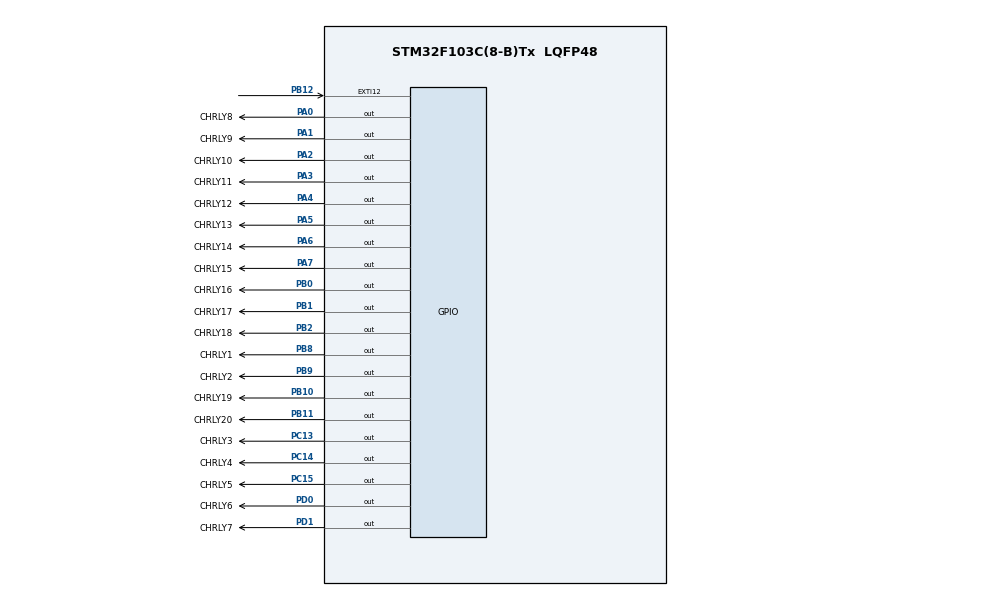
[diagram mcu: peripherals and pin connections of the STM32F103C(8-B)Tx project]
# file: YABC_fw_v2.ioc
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Mcu.Family=STM32F1
Mcu.Name=STM32F103C(8-B)Tx
Mcu.Package=LQFP48
NVIC.EXTI15_10_IRQn=true\:0\:0\:false\:false\:true\:true\:true\:true
NVIC.PriorityGroup=NVIC_PRIORITYGROUP_4
NVIC.TIM1_UP_IRQn=true\:0\:0\:false\:false\:true\:true\:true\:true
NVIC.TIM2_IRQn=true\:0\:0\:false\:false\:true\:true\:true\:true
PA0-WKUP.GPIO_Label=CHRLY8
PA0-WKUP.PinState=GPIO_PIN_RESET
PA0-WKUP.Signal=GPIO_Output
PA1.GPIO_Label=CHRLY9
PA1.PinState=GPIO_PIN_RESET
PA1.Signal=GPIO_Output
PA13.Mode=Serial_Wire
PA13.Signal=SYS_JTMS-SWDIO
PA14.Mode=Serial_Wire
PA14.Signal=SYS_JTCK-SWCLK
PA2.GPIO_Label=CHRLY10
PA2.PinState=GPIO_PIN_RESET
PA2.Signal=GPIO_Output
PA3.GPIO_Label=CHRLY11
PA3.PinState=GPIO_PIN_RESET
PA3.Signal=GPIO_Output
PA4.GPIO_Label=CHRLY12
PA4.PinState=GPIO_PIN_RESET
PA4.Signal=GPIO_Output
PA5.GPIO_Label=CHRLY13
PA5.PinState=GPIO_PIN_RESET
PA5.Signal=GPIO_Output
PA6.GPIO_Label=CHRLY14
PA6.PinState=GPIO_PIN_RESET
PA6.Signal=GPIO_Output
PA7.GPIO_Label=CHRLY15
PA7.PinState=GPIO_PIN_RESET
PA7.Signal=GPIO_Output
PB0.GPIO_Label=CHRLY16
PB0.PinState=GPIO_PIN_RESET
PB0.Signal=GPIO_Output
PB1.GPIO_Label=CHRLY17
PB1.PinState=GPIO_PIN_RESET
PB1.Signal=GPIO_Output
PB10.GPIO_Label=CHRLY19
PB10.PinState=GPIO_PIN_RESET
PB10.Signal=GPIO_Output
PB11.GPIO_Label=CHRLY20
PB11.PinState=GPIO_PIN_RESET
PB11.Signal=GPIO_Output
PB12.GPIO_ModeDefaultEXTI=GPIO_MODE_IT_RISING_FALLING
PB12.GPIO_PuPd=GPIO_PULLUP
PB12.Signal=GPXTI12
PB2.GPIO_Label=CHRLY18
PB2.PinState=GPIO_PIN_RESET
PB2.Signal=GPIO_Output
PB8.GPIO_Label=CHRLY1
PB8.PinState=GPIO_PIN_SET
PB8.Signal=GPIO_Output
PB9.GPIO_Label=CHRLY2
PB9.PinState=GPIO_PIN_RESET
PB9.Signal=GPIO_Output
PC13-TAMPER-RTC.GPIO_Label=CHRLY3
PC13-TAMPER-RTC.PinState=GPIO_PIN_RESET
PC13-TAMPER-RTC.Signal=GPIO_Output
PC14-OSC32_IN.GPIO_Label=CHRLY4
PC14-OSC32_IN.PinState=GPIO_PIN_RESET
PC14-OSC32_IN.Signal=GPIO_Output
PC15-OSC32_OUT.GPIO_Label=CHRLY5
PC15-OSC32_OUT.PinState=GPIO_PIN_RESET
PC15-OSC32_OUT.Signal=GPIO_Output
PD0-OSC_IN.GPIO_Label=CHRLY6
PD0-OSC_IN.PinState=GPIO_PIN_RESET
PD0-OSC_IN.Signal=GPIO_Output
PD1-OSC_OUT.GPIO_Label=CHRLY7
PD1-OSC_OUT.PinState=GPIO_PIN_RESET
PD1-OSC_OUT.Signal=GPIO_Output
ProjectManager.HeapSize=0x200
ProjectManager.StackSize=0x400
ProjectManager.TargetToolchain=STM32CubeIDE
RCC.AHBCLKDivider=RCC_SYSCLK_DIV2
RCC.AHBFreq_Value=4000000
RCC.APB1Freq_Value=4000000
RCC.APB1TimFreq_Value=4000000
RCC.APB2Freq_Value=4000000
RCC.APB2TimFreq_Value=4000000
RCC.HCLKFreq_Value=4000000
RCC.SYSCLKFreq_VALUE=8000000
RCC.SYSCLKSource=RCC_SYSCLKSOURCE_PLLCLK
RCC.USBFreq_Value=8000000
TIM1.Period=8
TIM1.Prescaler=49
TIM2.Period=20
TIM2.Prescaler=3999
VP_TIM1_VS_ClockSourceINT.Mode=Internal
VP_TIM2_VS_ClockSourceINT.Mode=Internal
board=custom

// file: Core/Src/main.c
/* USER CODE BEGIN Header */
/**
  ******************************************************************************
  * @file           : main.c
  * @brief          : Optimized Main program body for Charlieplexing (4MHz Low Power)
  ******************************************************************************
  */
/* USER CODE END Header */

#include "main.h"
#include <string.h>

// Ensure this header defines 'video_frames[ANIMATION_FRAMES][20][19]'
// #include "animations.h"

/* USER CODE BEGIN PTD */

// Represents the register state for one specific row/bit-plane
typedef struct {
    uint32_t PortA_CRL;
    // uint32_t PortA_CRH; // EXCLUDED to protect SWD (PA13/PA14)
    uint32_t PortA_ODR;

    uint32_t PortB_CRL;
    uint32_t PortB_CRH;
    uint32_t PortB_ODR;

    uint32_t PortC_CRL;
    uint32_t PortC_CRH;
    uint32_t PortC_ODR;

    uint32_t PortD_CRL;
    uint32_t PortD_CRH;
    uint32_t PortD_ODR;
} RowRegisterState;

// Physical Pin Definition
typedef struct {
    GPIO_TypeDef* port;
    uint8_t pinIndex;
} PinDef;

// Hardware Map for a Row
typedef struct {
    PinDef anode;
    PinDef cathodes[18];
} HardwareRowDef;

/* USER CODE END PTD */

/* USER CODE BEGIN PD */
#define COLOR_DEPTH 2    // 2-bit BCM (4 brightness levels: 0, 1, 2, 3)
#define ROW_COUNT 19
#define COL_COUNT 18

#define ANIMATION_FRAMES 1
/* USER CODE END PD */

TIM_HandleTypeDef htim1;
TIM_HandleTypeDef htim2;

/* USER CODE BEGIN PV */

// --- GLOBAL BUFFERS ---
// The ISR reads from here. Main loop writes to here.
RowRegisterState frameBufferLUT[ROW_COUNT][COLOR_DEPTH];

uint32_t bitDuration[COLOR_DEPTH];
volatile int current_frame_idx = 0;
volatile uint8_t update_frame_flag = 1; // Flag to trigger calculation

volatile uint8_t system_active = 1;
uint32_t last_activity_time = 0;

// --- HARDWARE PIN MAPPING ---
// The exact physical order of your Charlieplexing network (Pins 1-19)
const PinDef ALL_PINS[19] = {
    {GPIOB, 0}, {GPIOB, 1}, {GPIOB, 2},  {GPIOB, 3},  {GPIOB, 4},
    {GPIOB, 5}, {GPIOB, 6}, {GPIOB, 7},  {GPIOB, 8},  {GPIOB, 9},
    {GPIOB, 10},{GPIOB, 11},{GPIOB, 12}, {GPIOB, 13}, {GPIOB, 14},
    {GPIOB, 15},{GPIOC, 13},{GPIOC, 14}, {GPIOC, 15}
};

uint32_t video_frames[1][20][19] = {
	{0x0D, 0x1A, 0x27, 0x34, 0x41, 0x4E, 0x5B, 0x68, 0x075, 0x82, 0x8F, 0x9C, 0xA9, 0xB6, 0xC3, 0xD0, 0xDD, 0xEA, 0xF7},
	{0x0D, 0x1A, 0x27, 0x34, 0x41, 0x4E, 0x5B, 0x68, 0x075, 0x82, 0x8F, 0x9C, 0xA9, 0xB6, 0xC3, 0xD0, 0xDD, 0xEA, 0xF7},
	{0x0D, 0x1A, 0x27, 0x34, 0x41, 0x4E, 0x5B, 0x68, 0x075, 0x82, 0x8F, 0x9C, 0xA9, 0xB6, 0xC3, 0xD0, 0xDD, 0xEA, 0xF7},
	{0x0D, 0x1A, 0x27, 0x34, 0x41, 0x4E, 0x5B, 0x68, 0x075, 0x82, 0x8F, 0x9C, 0xA9, 0xB6, 0xC3, 0xD0, 0xDD, 0xEA, 0xF7},
	{0x0D, 0x1A, 0x27, 0x34, 0x41, 0x4E, 0x5B, 0x68, 0x075, 0x82, 0x8F, 0x9C, 0xA9, 0xB6, 0xC3, 0xD0, 0xDD, 0xEA, 0xF7},
	{0x0D, 0x1A, 0x27, 0x34, 0x41, 0x4E, 0x5B, 0x68, 0x075, 0x82, 0x8F, 0x9C, 0xA9, 0xB6, 0xC3, 0xD0, 0xDD, 0xEA, 0xF7},
	{0x0D, 0x1A, 0x27, 0x34, 0x41, 0x4E, 0x5B, 0x68, 0x075, 0x82, 0x8F, 0x9C, 0xA9, 0xB6, 0xC3, 0xD0, 0xDD, 0xEA, 0xF7},
	{0x0D, 0x1A, 0x27, 0x34, 0x41, 0x4E, 0x5B, 0x68, 0x075, 0x82, 0x8F, 0x9C, 0xA9, 0xB6, 0xC3, 0xD0, 0xDD, 0xEA, 0xF7},
	{0x0D, 0x1A, 0x27, 0x34, 0x41, 0x4E, 0x5B, 0x68, 0x075, 0x82, 0x8F, 0x9C, 0xA9, 0xB6, 0xC3, 0xD0, 0xDD, 0xEA, 0xF7},
	{0x0D, 0x1A, 0x27, 0x34, 0x41, 0x4E, 0x5B, 0x68, 0x075, 0x82, 0x8F, 0x9C, 0xA9, 0xB6, 0xC3, 0xD0, 0xDD, 0xEA, 0xF7},
	{0x0D, 0x1A, 0x27, 0x34, 0x41, 0x4E, 0x5B, 0x68, 0x075, 0x82, 0x8F, 0x9C, 0xA9, 0xB6, 0xC3, 0xD0, 0xDD, 0xEA, 0xF7},
	{0x0D, 0x1A, 0x27, 0x34, 0x41, 0x4E, 0x5B, 0x68, 0x075, 0x82, 0x8F, 0x9C, 0xA9, 0xB6, 0xC3, 0xD0, 0xDD, 0xEA, 0xF7},
	{0x0D, 0x1A, 0x27, 0x34, 0x41, 0x4E, 0x5B, 0x68, 0x075, 0x82, 0x8F, 0x9C, 0xA9, 0xB6, 0xC3, 0xD0, 0xDD, 0xEA, 0xF7},
	{0x0D, 0x1A, 0x27, 0x34, 0x41, 0x4E, 0x5B, 0x68, 0x075, 0x82, 0x8F, 0x9C, 0xA9, 0xB6, 0xC3, 0xD0, 0xDD, 0xEA, 0xF7},
	{0x0D, 0x1A, 0x27, 0x34, 0x41, 0x4E, 0x5B, 0x68, 0x075, 0x82, 0x8F, 0x9C, 0xA9, 0xB6, 0xC3, 0xD0, 0xDD, 0xEA, 0xF7},
	{0x0D, 0x1A, 0x27, 0x34, 0x41, 0x4E, 0x5B, 0x68, 0x075, 0x82, 0x8F, 0x9C, 0xA9, 0xB6, 0xC3, 0xD0, 0xDD, 0xEA, 0xF7},
	{0x0D, 0x1A, 0x27, 0x34, 0x41, 0x4E, 0x5B, 0x68, 0x075, 0x82, 0x8F, 0x9C, 0xA9, 0xB6, 0xC3, 0xD0, 0xDD, 0xEA, 0xF7},
	{0x0D, 0x1A, 0x27, 0x34, 0x41, 0x4E, 0x5B, 0x68, 0x075, 0x82, 0x8F, 0x9C, 0xA9, 0xB6, 0xC3, 0xD0, 0xDD, 0xEA, 0xF7},
	{0x0D, 0x1A, 0x27, 0x34, 0x41, 0x4E, 0x5B, 0x68, 0x075, 0x82, 0x8F, 0x9C, 0xA9, 0xB6, 0xC3, 0xD0, 0xDD, 0xEA, 0xF7},
	{0x0D, 0x1A, 0x27, 0x34, 0x41, 0x4E, 0x5B, 0x68, 0x075, 0x82, 0x8F, 0x9C, 0xA9, 0xB6, 0xC3, 0xD0, 0xDD, 0xEA, 0xF7}
};

/* USER CODE END PV */

void SystemClock_Config(void);
static void MX_GPIO_Init(void);
static void MX_TIM1_Init(void);
static void MX_TIM2_Init(void);

/* USER CODE BEGIN PFP */
void initBitDurationLUT(void);
void GetHardwareRow(int rowIndex, HardwareRowDef *rowDef);
void PrecomputeFrame(void);
/* USER CODE END PFP */

int main(void)
{
  HAL_Init();

  // 1. Configure System Clock to 4 MHz (Low Power)
  SystemClock_Config();

  initBitDurationLUT();

  MX_GPIO_Init();
  MX_TIM1_Init();
  MX_TIM2_Init();

  // 2. Initial Frame Calculation
  PrecomputeFrame();

  // 3. Start Timers
  HAL_TIM_Base_Start_IT(&htim1); // LED Refresh (High Speed)
  HAL_TIM_Base_Start_IT(&htim2); // Animation Tick (Low Speed)

  last_activity_time = HAL_GetTick();

  while (1)
  {
    // --- SLEEP LOGIC (10 Seconds Timeout) ---
    if(system_active && (HAL_GetTick() - last_activity_time > 10000)){
        system_active = 0;

        // Disable Timers to stop interrupts
        HAL_TIM_Base_Stop_IT(&htim1);
        HAL_TIM_Base_Stop_IT(&htim2);

        // Turn off all LEDs (Reset ODRs to safe state)
        GPIOA->ODR = (1<<0);  // Keep PA0 Pull-Up active! (New wakeup button)
        GPIOB->ODR = 0;
        GPIOC->ODR = 0;
        GPIOD->ODR = 0;

        // Enter Stop Mode
        HAL_SuspendTick();
        HAL_PWR_EnterSTOPMode(PWR_LOWPOWERREGULATOR_ON, PWR_STOPENTRY_WFI);

        // --- WAKE UP POINT ---
        SystemClock_Config(); // Restore 4 MHz clock
        HAL_ResumeTick();

        system_active = 1;
        last_activity_time = HAL_GetTick();

        // Restart Timers
        HAL_TIM_Base_Start_IT(&htim1);
        HAL_TIM_Base_Start_IT(&htim2);
    }

    // --- RENDER LOGIC ---
    // Only calculate when TIM2 says the frame has changed
    if(system_active && update_frame_flag) {
        PrecomputeFrame();
        update_frame_flag = 0;
    }
  }
}

/**
  * @brief  ISR for LED Refresh (TIM1)
  * @note   Extremely optimized register dump. No logic here.
  */
void HAL_TIM_PeriodElapsedCallback(TIM_HandleTypeDef* htim)
{
    static int row = 0;
    static int bit = 0;

    if(htim->Instance == TIM1) // LED Refresh
    {
        // Pointer to the pre-calculated register state
        RowRegisterState *state = &frameBufferLUT[row][bit];

        // 1. Dump Registers (Takes ~20 cycles)
        GPIOA->CRL = state->PortA_CRL;
        // GPIOA->CRH = state->PortA_CRH; // DISABLED FOR SWD SAFETY
        GPIOA->ODR = state->PortA_ODR;

        GPIOB->CRL = state->PortB_CRL;
        GPIOB->CRH = state->PortB_CRH;
        GPIOB->ODR = state->PortB_ODR;

        GPIOC->CRL = state->PortC_CRL;
        GPIOC->CRH = state->PortC_CRH;
        GPIOC->ODR = state->PortC_ODR;

        GPIOD->CRL = state->PortD_CRL;
        GPIOD->CRH = state->PortD_CRH;
        GPIOD->ODR = state->PortD_ODR;

        // 2. Advance Counters
        row++;
        if(row >= ROW_COUNT)
        {
            row = 0;
            bit++;
            if(bit >= COLOR_DEPTH) bit = 0;

            TIM1->ARR = bitDuration[bit]; // Update BAM timing
        }
    }

    if(htim->Instance == TIM2) // Animation Tick
    {
        current_frame_idx++;
        if (current_frame_idx >= ANIMATION_FRAMES) {
            current_frame_idx = 0;
        }
        update_frame_flag = 1; // Tell Main loop to calculate next frame
    }
}

/**
  * @brief  Calculates the LUT for the current frame based on 8-bit input.
  * Runs in Main Loop.
  */
void PrecomputeFrame(void) {
    const uint32_t DEFAULT_CRL = 0x44444444;
    const uint32_t DEFAULT_CRH = 0x44444444;

    // SAFETY FOR PA0: Default CRL for Port A must set Pin 0 to Input Pull-Up/Down (0x8)
    const uint32_t PORTA_CRL_SAFE = 0x44444448;
    const uint32_t PORTA_ODR_SAFE = (1 << 0); // Pull-Up selected

    HardwareRowDef rowHardware;

    // Pre-calculate the divisor for thresholding
    // For Depth 2 (4 levels): 256 / 4 = 64.
    uint8_t divisor = 256 / (1 << COLOR_DEPTH);

    for(int row = 0; row < ROW_COUNT; row++) {
        GetHardwareRow(row, &rowHardware);

        for(int bitPlane = 0; bitPlane < COLOR_DEPTH; bitPlane++) {

            RowRegisterState *state = &frameBufferLUT[row][bitPlane];

            // 1. Reset State to Safe Defaults
            state->PortA_CRL = PORTA_CRL_SAFE; // PA0 Safety
            state->PortA_ODR = PORTA_ODR_SAFE; // PA0 Safety

            state->PortB_CRL = DEFAULT_CRL;
            state->PortB_CRH = DEFAULT_CRH;
            state->PortB_ODR = 0;

            state->PortC_CRL = DEFAULT_CRL;
            state->PortC_CRH = DEFAULT_CRH;
            state->PortC_ODR = 0;

            state->PortD_CRL = DEFAULT_CRL;
            state->PortD_CRH = DEFAULT_CRH;
            state->PortD_ODR = 0;

            // 2. Configure ANODE (Active High)
            PinDef anode = rowHardware.anode;

            // Determine Port Pointers
            uint32_t *crl = (anode.pinIndex < 8) ? ((anode.port == GPIOA) ? &state->PortA_CRL : (anode.port == GPIOB) ? &state->PortB_CRL : (anode.port == GPIOC) ? &state->PortC_CRL : &state->PortD_CRL)
                                                 : ((anode.port == GPIOA) ? NULL : (anode.port == GPIOB) ? &state->PortB_CRH : (anode.port == GPIOC) ? &state->PortC_CRH : &state->PortD_CRH);

            uint32_t *odr = (anode.port == GPIOA) ? &state->PortA_ODR : (anode.port == GPIOB) ? &state->PortB_ODR : (anode.port == GPIOC) ? &state->PortC_ODR : &state->PortD_ODR;

            if(crl) {
                uint8_t shift = (anode.pinIndex % 8) * 4;
                *crl &= ~(0xF << shift);
                *crl |=  (0x2 << shift); // Output 2MHz
                *odr |=  (1 << anode.pinIndex); // HIGH
            }

            // 3. Configure CATHODES (Active Low)
            for(int col = 0; col < COL_COUNT; col++) {

                // --- THRESHOLD LOGIC ---
                uint8_t rawBrightness = video_frames[current_frame_idx][row][col];

                // Map 0-255 to 0-3 (if depth 2)
                uint8_t pixelLevel = rawBrightness / divisor;

                // Extract BCM bit
                if( (pixelLevel >> bitPlane) & 0x01 ) {

                    PinDef cathode = rowHardware.cathodes[col];

                    uint32_t *c_crl = (cathode.pinIndex < 8) ? ((cathode.port == GPIOA) ? &state->PortA_CRL : (cathode.port == GPIOB) ? &state->PortB_CRL : (cathode.port == GPIOC) ? &state->PortC_CRL : &state->PortD_CRL)
                                                             : ((cathode.port == GPIOA) ? NULL : (cathode.port == GPIOB) ? &state->PortB_CRH : (cathode.port == GPIOC) ? &state->PortC_CRH : &state->PortD_CRH);

                    uint32_t *c_odr = (cathode.port == GPIOA) ? &state->PortA_ODR : (cathode.port == GPIOB) ? &state->PortB_ODR : (cathode.port == GPIOC) ? &state->PortC_ODR : &state->PortD_ODR;

                    if(c_crl) {
                        uint8_t c_shift = (cathode.pinIndex % 8) * 4;
                        *c_crl &= ~(0xF << c_shift);
                        *c_crl |=  (0x2 << c_shift); // Output
                        *c_odr &= ~(1 << cathode.pinIndex); // LOW
                    }
                }
            }
        }
    }
}

// Helper to map Row Index -> Hardware Pins
void GetHardwareRow(int rowIndex, HardwareRowDef *rowDef) {
    int anodeIndex = 18 - rowIndex;
    rowDef->anode = ALL_PINS[anodeIndex];

    int cathodeCount = 0;
    for (int i = 0; i < 19; i++) {
        if (i == anodeIndex) continue;
        rowDef->cathodes[cathodeCount++] = ALL_PINS[i];
    }
}

// 4 MHz System Clock Config
void SystemClock_Config(void)
{
  RCC_OscInitTypeDef RCC_OscInitStruct = {0};
  RCC_ClkInitTypeDef RCC_ClkInitStruct = {0};

  // 1. Use HSI (8 MHz) directly, no PLL needed for low speed
  RCC_OscInitStruct.OscillatorType = RCC_OSCILLATORTYPE_HSI;
  RCC_OscInitStruct.HSIState = RCC_HSI_ON;
  RCC_OscInitStruct.HSICalibrationValue = RCC_HSICALIBRATION_DEFAULT;
  RCC_OscInitStruct.PLL.PLLState = RCC_PLL_NONE; // PLL Off
  if (HAL_RCC_OscConfig(&RCC_OscInitStruct) != HAL_OK) Error_Handler();

  // 2. Set SysClk to HSI, divide AHB by 2 to get 4 MHz
  RCC_ClkInitStruct.ClockType = RCC_CLOCKTYPE_HCLK|RCC_CLOCKTYPE_SYSCLK
                              |RCC_CLOCKTYPE_PCLK1|RCC_CLOCKTYPE_PCLK2;
  RCC_ClkInitStruct.SYSCLKSource = RCC_SYSCLKSOURCE_HSI; // 8 MHz
  RCC_ClkInitStruct.AHBCLKDivider = RCC_SYSCLK_DIV2;     // 8 MHz / 2 = 4 MHz System Clock
  RCC_ClkInitStruct.APB1CLKDivider = RCC_HCLK_DIV1;
  RCC_ClkInitStruct.APB2CLKDivider = RCC_HCLK_DIV1;

  if (HAL_RCC_ClockConfig(&RCC_ClkInitStruct, FLASH_LATENCY_0) != HAL_OK) Error_Handler();
}

void initBitDurationLUT(void){
    // Optimized for 4MHz Clock, Prescaler 49 (12.5us ticks)
    uint32_t multiplier = 15;

    for(uint32_t i = 0; i < COLOR_DEPTH; i++){
        bitDuration[i] = (1 << i) * multiplier;
    }
}

static void MX_TIM1_Init(void)
{
  TIM_ClockConfigTypeDef sClockSourceConfig = {0};
  TIM_MasterConfigTypeDef sMasterConfig = {0};

  htim1.Instance = TIM1;
  // Prescaler 49: 4MHz / 50 = 80 KHz (12.5us per tick)
  htim1.Init.Prescaler = 49;
  htim1.Init.CounterMode = TIM_COUNTERMODE_UP;
  htim1.Init.Period = 8;
  htim1.Init.ClockDivision = TIM_CLOCKDIVISION_DIV1;
  htim1.Init.RepetitionCounter = 0;
  htim1.Init.AutoReloadPreload = TIM_AUTORELOAD_PRELOAD_DISABLE;
  if (HAL_TIM_Base_Init(&htim1) != HAL_OK) Error_Handler();

  sClockSourceConfig.ClockSource = TIM_CLOCKSOURCE_INTERNAL;
  if (HAL_TIM_ConfigClockSource(&htim1, &sClockSourceConfig) != HAL_OK) Error_Handler();

  sMasterConfig.MasterOutputTrigger = TIM_TRGO_RESET;
  sMasterConfig.MasterSlaveMode = TIM_MASTERSLAVEMODE_DISABLE;
  if (HAL_TIMEx_MasterConfigSynchronization(&htim1, &sMasterConfig) != HAL_OK) Error_Handler();
}

static void MX_TIM2_Init(void)
{
  TIM_ClockConfigTypeDef sClockSourceConfig = {0};
  TIM_MasterConfigTypeDef sMasterConfig = {0};

  htim2.Instance = TIM2;
  htim2.Init.Prescaler = 3999;
  htim2.Init.CounterMode = TIM_COUNTERMODE_UP;
  htim2.Init.Period = 20;
  htim2.Init.ClockDivision = TIM_CLOCKDIVISION_DIV1;
  htim2.Init.AutoReloadPreload = TIM_AUTORELOAD_PRELOAD_DISABLE;
  if (HAL_TIM_Base_Init(&htim2) != HAL_OK) Error_Handler();

  sClockSourceConfig.ClockSource = TIM_CLOCKSOURCE_INTERNAL;
  if (HAL_TIM_ConfigClockSource(&htim2, &sClockSourceConfig) != HAL_OK) Error_Handler();

  sMasterConfig.MasterOutputTrigger = TIM_TRGO_RESET;
  sMasterConfig.MasterSlaveMode = TIM_MASTERSLAVEMODE_DISABLE;
  if (HAL_TIMEx_MasterConfigSynchronization(&htim2, &sMasterConfig) != HAL_OK) Error_Handler();
}

static void MX_GPIO_Init(void)
{
  GPIO_InitTypeDef GPIO_InitStruct = {0};

  /* GPIO Ports Clock Enable */
  __HAL_RCC_GPIOC_CLK_ENABLE();
  __HAL_RCC_GPIOD_CLK_ENABLE();
  __HAL_RCC_GPIOA_CLK_ENABLE();
  __HAL_RCC_GPIOB_CLK_ENABLE();

  /* Configure PA0 for Wakeup Button */
  GPIO_InitStruct.Pin = GPIO_PIN_0;
  GPIO_InitStruct.Mode = GPIO_MODE_IT_RISING_FALLING;
  GPIO_InitStruct.Pull = GPIO_PULLUP;
  HAL_GPIO_Init(GPIOA, &GPIO_InitStruct);

  /* EXTI interrupt init*/
  HAL_NVIC_SetPriority(EXTI0_IRQn, 0, 0);
  HAL_NVIC_EnableIRQ(EXTI0_IRQn);
}

void HAL_GPIO_EXTI_Callback(uint16_t GPIO_Pin)
{
    if (GPIO_Pin == GPIO_PIN_0) {
        last_activity_time = HAL_GetTick();
    }
}

void Error_Handler(void)
{
  __disable_irq();
  while (1) {}
}
